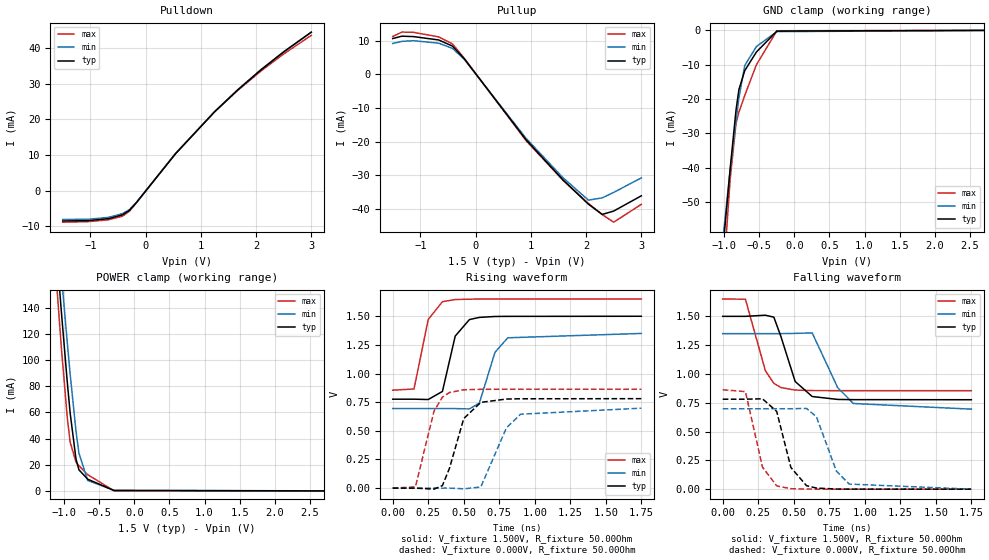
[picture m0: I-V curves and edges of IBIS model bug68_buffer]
[IBIS Ver]   3.2
[File Name]   bug68a.ibs
[File Rev]   0.00
[Date]   05/30/2002
[Source]   From silicon level SPICE model at Intel Corporation.
[Notes]   The following information represents a test case for
   illustrating an IBIS parser bug and not a real device.
[Disclaimer]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
[Copyright]   Copyright (C) 2002, Intel Corporation.
[Component]   BUG68
[Manufacturer]  Intel Corporation
[Package]
|   typ   min   max
R_pkg   0.000Ohm   0.000Ohm   0.000Ohm
L_pkg   0.00H   0.00H   0.00H
C_pkg   0.00F   0.00F   0.00F
[Pin]  signal_name  model_name   R_pin  L_pin  C_pin
1   bug68   bug68_buffer
| Models and submodels in the file (1): bug68_buffer (I/O)
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[Model]   bug68_buffer
Model_type   I/O
Vinl = 800.000mV
Vinh = 2.000V
Vmeas = 1.500V
Cref = 0.000F
|   typ   min   max
C_comp   1.790pF   1.730pF   1.800pF
[Voltage Range]   1.500V   1.350V   1.650V
[Temperature Range]   60.0   125.0   -10.0
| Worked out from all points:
|   slope of the pulldown table from 0 to 0.225 V, typ, clamps not added: 50.4 ohm
|   slope of the pullup table from 0 to 0.225 V, typ, clamps not added: 43.8 ohm
|   GND clamp passes 1 mA (typ) near -0.32 V on its own axis
|   POWER clamp passes 1 mA (typ) near -0.36 V on its own axis
|   falling waveform, V_fixture 1.500V, R_fixture 50.00Ohm: 20-80 % time 113ps typ, 140ps min, 102ps max; typ from 1.5 V to 0.776 V
|   rising waveform, V_fixture 1.500V, R_fixture 50.00Ohm: 20-80 % time 84.6ps typ, 98.4ps min, 74.4ps max; typ from 0.776 V to 1.5 V
|   rising waveform, V_fixture 0.000V, R_fixture 50.00Ohm: 20-80 % time 112ps typ, 132ps min, 94.2ps max; typ from 0 V to 0.781 V
|   falling waveform, V_fixture 0.000V, R_fixture 50.00Ohm: 20-80 % time 101ps typ, 126ps min, 90ps max; typ from 0.781 V to 0 V
[Pulldown]
|   Voltage   I(typ)   I(min)   I(max)
-1.499V   -8.452mA   -8.022mA   -8.795mA
-1.042V   -8.358mA   -7.992mA   -8.648mA
-666.7mV  -7.795mA   -7.439mA   -8.114mA
-416.7mV  -6.733mA   -6.388mA   -7.099mA
-291.7mV  -5.485mA   -5.259mA   -5.725mA
-166.7mV  -3.321mA   -3.298mA   -3.388mA
541.7mV   10.36mA    10.4mA     10.48mA
1.25V     22.14mA    22.2mA     22.15mA
1.667V    28.24mA    28.31mA    28.11mA
2.083V    33.82mA    33.88mA    33.48mA
2.5V      38.91mA    38.96mA    38.34mA
3V        44.45mA    44.47mA    43.56mA
[GND Clamp]
|   Voltage   I(typ)   I(min)   I(max)
-1.499V   -330.5mA   -298.3mA   -391.8mA
-1.167V   -106.3mA   -97.23mA   -127.9mA
-1.125V   -92.51mA   -85.34mA   -110.4mA
-1.083V   -80.05mA   -74.59mA   -94.78mA
-1.042V   -68.9mA    -64.95mA   -80.76mA
-916.7mV  -40.38mA   -40.84mA   -43.4mA
-833.3mV  -23.33mA   -26.52mA   -27.21mA
-791.7mV  -17.29mA   -19.71mA   -23.85mA
-708.3mV  -11.73mA   -10.25mA   -18.97mA
-541.7mV  -6.303mA   -4.712mA   -10mA
-250mV    -227.9uA   -377.5uA   -123.3uA
3V        0A         0A         0A
[Pullup]
|   Voltage   I(typ)   I(min)   I(max)
-1.499V   10.72mA    9.252mA    11.32mA
-1.333V   11.43mA    9.884mA    12.65mA
-1.125V   11.31mA    10.08mA    12.58mA
-666.7mV  10.3mA     9.349mA    11.22mA
-416.7mV  8.465mA    7.786mA    9.112mA
-208.3mV  4.777mA    4.613mA    4.932mA
916.7mV   -19.51mA   -19.1mA    -19.8mA
1.583V    -31.47mA   -30.81mA   -31.56mA
2.042V    -38.69mA   -37.49mA   -38.45mA
2.292V    -41.75mA   -36.81mA   -41.79mA
2.5V      -40.75mA   -35.19mA   -44.07mA
3V        -36.2mA    -30.84mA   -38.74mA
[POWER Clamp]
|   Voltage   I(typ)   I(min)   I(max)
-1.499V   554.6mA    575.2mA    542.2mA
-1.167V   222.2mA    245.7mA    201mA
-1.125V   193.3mA    218.3mA    169.8mA
-1.083V   164.8mA    191.4mA    139.1mA
-1.042V   136.9mA    165mA      109.4mA
-958.3mV  83.54mA    113.7mA    56.37mA
-916.7mV  59.49mA    89.27mA    37.28mA
-833.3mV  24.36mA    45.73mA    21.99mA
-791.7mV  16.15mA    28.92mA    19.22mA
-666.7mV  8.964mA    8.004mA    12.42mA
-291.7mV  307.6uA    511.8uA    143.1uA
3V        0A         0A         0A
[Ramp]
R_load = 50.00Ohm
|   typ   min   max
dV/dt_r   468.484mV/112.036ps 418.752mV/131.571ps 517.800mV/94.176ps
dV/dt_f   434.188mV/113.313ps 393.268mV/139.574ps 477.088mV/102.077ps
[Falling Waveform]
V_fixture = 1.500V
V_fixture_min = 1.350V
V_fixture_max = 1.650V
R_fixture = 50.00Ohm
|   Time   V(typ)   V(min)   V(max)
0s        1.5V       1.35V      1.65V
160ps     1.5V       1.35V      1.649V
300ps     1.51V      1.35V      1.029V
360ps     1.493V     1.35V      918.3mV
410ps     1.324V     1.35V      882.1mV
510ps     934.6mV    1.352V     860.1mV
630ps     804.1mV    1.356V     855.7mV
810ps     778.9mV    879.5mV    854.9mV
920ps     777mV      743.6mV    854.9mV
1.75ns    776.3mV    694.5mV    854.9mV
[Rising Waveform]
V_fixture = 1.500V
V_fixture_min = 1.350V
V_fixture_max = 1.650V
R_fixture = 50.00Ohm
|   Time   V(typ)   V(min)   V(max)
0s        776.3mV    694.5mV    854.9mV
150ps     776.3mV    694.5mV    865.3mV
250ps     773.3mV    694.5mV    1.472V
350ps     843.8mV    694.5mV    1.627V
440ps     1.327V     694.4mV    1.646V
540ps     1.471V     691.2mV    1.649V
610ps     1.49V      742.7mV    1.65V
720ps     1.498V     1.186V     1.65V
810ps     1.499V     1.312V     1.65V
1.75ns    1.5V       1.35V      1.65V
[Rising Waveform]
V_fixture = 0.000V
V_fixture_min = 0.000V
V_fixture_max = 0.000V
R_fixture = 50.00Ohm
|   Time   V(typ)   V(min)   V(max)
0s        5.642uV    29.96uV    1.024uV
160ps     -552.5nV   29.96uV    11.06mV
290ps     -8.995mV   29.93uV    669.8mV
350ps     22.07mV    15.65uV    795.1mV
400ps     175.2mV    385uV      834.7mV
500ps     607.1mV    -6.063mV   858mV
620ps     748.4mV    9.618mV    862.3mV
800ps     777.4mV    525.4mV    863mV
900ps     779.8mV    645.1mV    863mV
1.75ns    780.8mV    697.9mV    863mV
[Falling Waveform]
V_fixture = 0.000V
V_fixture_min = 0.000V
V_fixture_max = 0.000V
R_fixture = 50.00Ohm
|   Time   V(typ)   V(min)   V(max)
0s        780.8mV    697.9mV    863mV
160ps     780.8mV    697.9mV    846.6mV
280ps     784.4mV    697.9mV    191.4mV
380ps     674.7mV    697.9mV    27.96mV
480ps     188.2mV    698mV      4.209mV
590ps     30.01mV    700.9mV    562uV
660ps     9.603mV    627.5mV    166.7uV
800ps     1.08mV     157.4mV    18.77uV
890ps     296.6uV    44.12mV    5.918uV
1.75ns    5.642uV    29.96uV    1.024uV
